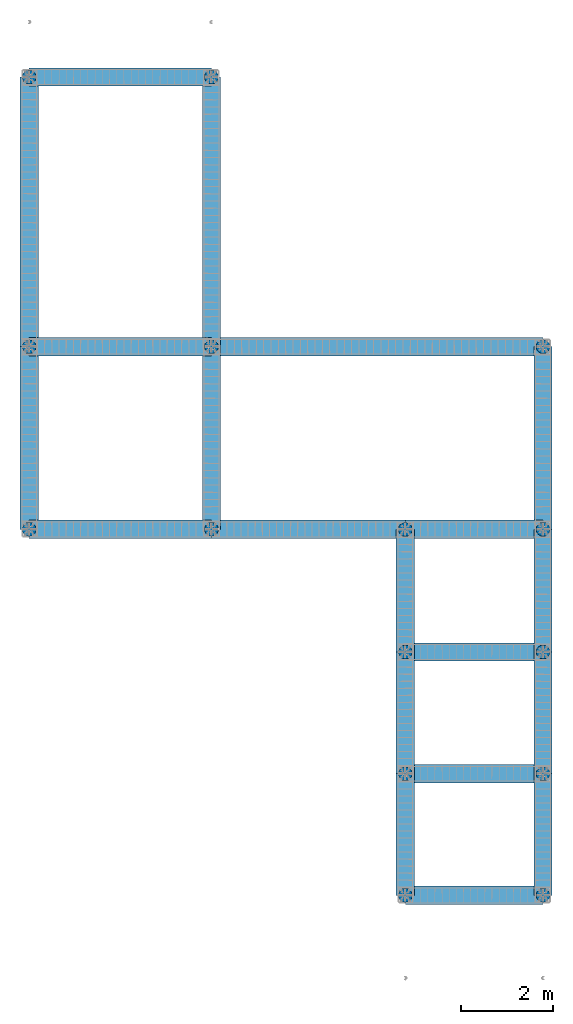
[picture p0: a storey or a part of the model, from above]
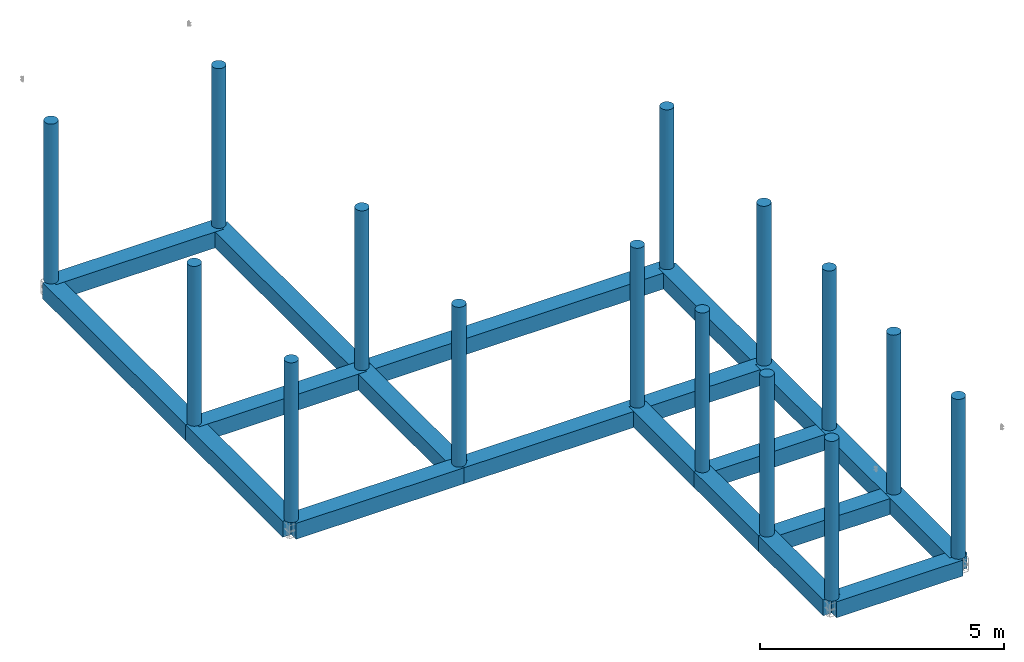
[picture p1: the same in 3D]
Properties of the parts of a building model (IFC4), part 1 of 2

# File
Description: ViewDefinition [CoordinationView]
Made in: IFC file generated by ModeSt (Tecnisoft s.a.s.)

# IfcBuildingStorey (2)
In: Tettoia
Name | Elevation (m)
Storey 0 | 0
Storey 1 | 4.2

# IfcBeam: 2 TRAVE 40X40 (20)
In: Storey 0
Type - PredefinedType: BEAM; Material: Calcestruzzo classe C25/30
Description: 2 TRAVE 40X40 - Cemento armato
Pset_BeamCommon - LoadBearing: yes
BaseQuantities - ?: 0.16 m2
Name | BaseQuantities, ? (m3) | BaseQuantities, ? (m)
406 | 0.6352 | 3.97
410 | 0.6368 | 3.98
405 | 0.48 | 3
404 | 0.48 | 3
403 | 0.48 | 3
402 | 0.48 | 3
2 x 412 | 0.424 | 2.65
412 | 0.4272 | 2.67
412 | 0.6368 | 3.98
406 | 1.1552 | 7.22
410 | 0.9392 | 5.87
407 | 0.6352 | 3.97
409 | 0.9392 | 5.87
409 | 0.6368 | 3.98
405 | 0.6352 | 3.97
405 | 0.6752 | 4.22
411 | 0.4272 | 2.67
2 x 411 | 0.424 | 2.65

# IfcBeam: 3 IPE160 (6)
In: Storey 1
Type - PredefinedType: BEAM; Material: Acciaio
Description: 3 IPE160 - Acciaio
Pset_BeamCommon - LoadBearing: yes
BaseQuantities - ?: 0.0019396 m2
Name | BaseQuantities, ? (m3) | BaseQuantities, ? (m)
102 | 0.0058188 | 3
101 | 0.0058188 | 3
107 | 0.00770022 | 3.97
108 | 0.00770022 | 3.97
104 | 0.0058188 | 3
103 | 0.0058188 | 3

# IfcBeam: 9 IPE200 (28)
In: Storey 1
Type - PredefinedType: BEAM; Material: Acciaio
Description: 9 IPE200 - Acciaio
Pset_BeamCommon - LoadBearing: yes
BaseQuantities - ?: 0.0027248 m2
Name | BaseQuantities, ? (m3) | BaseQuantities, ? (m)
106 | 0.0108175 | 3.97
109 | 0.00799729 | 2.935
106 | 0.0081744 | 3
110 | 0.00381472 | 1.4
110 | 0.00799729 | 2.935
109 | 0.0108447 | 3.98
105 | 0.0108175 | 3.97
105 | 0.0114987 | 4.22
110 | 0.0108447 | 3.98
109 | 0.00381472 | 1.4
110 | 0.00799728 | 2.935
109 | 0.00799728 | 2.935
2 x 112 | 0.00361036 | 1.325
105 | 0.0081744 | 3
111 | 0.00727521 | 2.67
2 x 111 | 0.00361036 | 1.325
111 | 0.00722072 | 2.65
111 | 0.0054496 | 2
112 | 0.0108447 | 3.98
112 | 0.00727521 | 2.67
105 | 0.00054496 | 0.2
112 | 0.000544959 | 0.2
111 | 0.0108447 | 3.98
106 | 0.0114987 | 4.22
112 | 0.00722072 | 2.65
112 | 0.0054496 | 2

# IfcColumn: 1 PILASTRO D30 (15)
In: Storey 0
Type - PredefinedType: COLUMN; Material: Calcestruzzo classe C25/30
Description: 1 PILASTRO D30 - Cemento armato
Pset_ColumnCommon - LoadBearing: yes
BaseQuantities - ?: 0.0695288 m2; ?: 0.278115 m3; ?: 4 m
Name
5
6
4
3
8
12
13
15
14
1
9
22
23
2
26

# IfcColumn: 4 CC101x5 (15)
In: Storey 1
Type - PredefinedType: COLUMN; Material: Acciaio
Description: 4 CC101x5 - Acciaio
Pset_ColumnCommon - LoadBearing: yes
BaseQuantities - ?: 0.00148328 m2; ?: 0.000296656 m3; ?: 0.2 m
Name
16
17
18
19
11
7
20
21
10
24
25
27
28
29
30

# IfcFastener: Collegamento -001_0101 (40)
In: Storey 1
Type - PredefinedType: WELD
Description: 7x7

# IfcFastener: Collegamento -002_0102 (40)
In: Storey 1
Type - PredefinedType: WELD
Description: 7x7

# IfcFastener: Collegamento -003_0103 (40)
In: Storey 1
Type - PredefinedType: WELD
Description: 7x7

# IfcFastener: Collegamento -004_0104 (40)
In: Storey 1
Type - PredefinedType: WELD
Description: 7x7

# IfcFastener: Collegamento -005_0105 (40)
In: Storey 1
Type - PredefinedType: WELD
Description: 7x7

# IfcFastener: Collegamento -006_0106 (40)
In: Storey 1
Type - PredefinedType: WELD
Description: 7x7

# IfcFastener: Collegamento -007_0107 (40)
In: Storey 1
Type - PredefinedType: WELD
Description: 7x7

# IfcFastener: Collegamento -008_0108 (40)
In: Storey 1
Type - PredefinedType: WELD
Description: 7x7

# IfcFastener: Collegamento -009_0109 (40)
In: Storey 1
Type - PredefinedType: WELD
Description: 7x7

# IfcFastener: Collegamento -010_0110 (40)
In: Storey 1
Type - PredefinedType: WELD
Description: 7x7

# IfcFastener: Collegamento -011_0111 (40)
In: Storey 1
Type - PredefinedType: WELD
Description: 7x7

# IfcFastener: Collegamento -012_0112 (40)
In: Storey 1
Type - PredefinedType: WELD
Description: 7x7

# IfcFastener: Collegamento -013_0113 (40)
In: Storey 1
Type - PredefinedType: WELD
Description: 7x7

# IfcFastener: Collegamento -014_0114 (40)
In: Storey 1
Type - PredefinedType: WELD
Description: 7x7

# IfcFastener: Collegamento -015_0115 (40)
In: Storey 1
Type - PredefinedType: WELD
Description: 7x7

# IfcFastener: Collegamento 0101_-001 (40)
In: Storey 1
Type - PredefinedType: WELD
Description: 7x7

# IfcFastener: Collegamento 0102_-002 (40)
In: Storey 1
Type - PredefinedType: WELD
Description: 7x7

# IfcFastener: Collegamento 0103_-003 (40)
In: Storey 1
Type - PredefinedType: WELD
Description: 7x7

# IfcFastener: Collegamento 0104_-004 (40)
In: Storey 1
Type - PredefinedType: WELD
Description: 7x7

# IfcFastener: Collegamento 0105_-005 (40)
In: Storey 1
Type - PredefinedType: WELD
Description: 7x7

# IfcFastener: Collegamento 0106_-006 (40)
In: Storey 1
Type - PredefinedType: WELD
Description: 7x7

# IfcFastener: Collegamento 0107_-007 (40)
In: Storey 1
Type - PredefinedType: WELD
Description: 7x7

# IfcFastener: Collegamento 0108_-008 (40)
In: Storey 1
Type - PredefinedType: WELD
Description: 7x7

# IfcFastener: Collegamento 0109_-009 (40)
In: Storey 1
Type - PredefinedType: WELD
Description: 7x7

# IfcFastener: Collegamento 0110_-010 (40)
In: Storey 1
Type - PredefinedType: WELD
Description: 7x7

# IfcFastener: Collegamento 0111_-011 (40)
In: Storey 1
Type - PredefinedType: WELD
Description: 7x7

# IfcFastener: Collegamento 0112_-012 (40)
In: Storey 1
Type - PredefinedType: WELD
Description: 7x7

# IfcFastener: Collegamento 0113_-013 (40)
In: Storey 1
Type - PredefinedType: WELD
Description: 7x7

# IfcFastener: Collegamento 0114_-014 (40)
In: Storey 1
Type - PredefinedType: WELD
Description: 7x7

# IfcFastener: Collegamento 0115_-015 (40)
In: Storey 1
Type - PredefinedType: WELD
Description: 7x7

# IfcMechanicalFastener: Collegamento -001_0101 (30)
In: Storey 1
Type - PredefinedType: BOLT
Name | Description | NominalDiameter (m)
18 x Collegamento -001_0101 | M12 | 0.0119999
12 x Collegamento -001_0101 | M24 | 0.024

# IfcMechanicalFastener: Collegamento -002_0102 (30)
In: Storey 1
Type - PredefinedType: BOLT
Name | Description | NominalDiameter (m)
18 x Collegamento -002_0102 | M12 | 0.0119999
12 x Collegamento -002_0102 | M24 | 0.024

# IfcMechanicalFastener: Collegamento -003_0103 (30)
In: Storey 1
Type - PredefinedType: BOLT
Name | Description | NominalDiameter (m)
18 x Collegamento -003_0103 | M12 | 0.0119999
12 x Collegamento -003_0103 | M24 | 0.024

# IfcMechanicalFastener: Collegamento -004_0104 (30)
In: Storey 1
Type - PredefinedType: BOLT
Name | Description | NominalDiameter (m)
18 x Collegamento -004_0104 | M12 | 0.0119999
12 x Collegamento -004_0104 | M24 | 0.024

# IfcMechanicalFastener: Collegamento -005_0105 (30)
In: Storey 1
Type - PredefinedType: BOLT
Name | Description | NominalDiameter (m)
18 x Collegamento -005_0105 | M12 | 0.0119999
12 x Collegamento -005_0105 | M24 | 0.024

# IfcMechanicalFastener: Collegamento -006_0106 (30)
In: Storey 1
Type - PredefinedType: BOLT
Name | Description | NominalDiameter (m)
18 x Collegamento -006_0106 | M12 | 0.0119999
12 x Collegamento -006_0106 | M24 | 0.024

# IfcMechanicalFastener: Collegamento -007_0107 (30)
In: Storey 1
Type - PredefinedType: BOLT
Name | Description | NominalDiameter (m)
6 x Collegamento -007_0107 | M12 | 0.0119991
12 x Collegamento -007_0107 | M24 | 0.024
12 x Collegamento -007_0107 | M12 | 0.0119998

# IfcMechanicalFastener: Collegamento -008_0108 (30)
In: Storey 1
Type - PredefinedType: BOLT
Name | Description | NominalDiameter (m)
6 x Collegamento -008_0108 | M12 | 0.0119991
12 x Collegamento -008_0108 | M24 | 0.024
12 x Collegamento -008_0108 | M12 | 0.0119997

# IfcMechanicalFastener: Collegamento -009_0109 (30)
In: Storey 1
Type - PredefinedType: BOLT
Name | Description | NominalDiameter (m)
6 x Collegamento -009_0109 | M12 | 0.0119991
12 x Collegamento -009_0109 | M24 | 0.024
12 x Collegamento -009_0109 | M12 | 0.0119997

# IfcMechanicalFastener: Collegamento -010_0110 (30)
In: Storey 1
Type - PredefinedType: BOLT
Name | Description | NominalDiameter (m)
6 x Collegamento -010_0110 | M12 | 0.0119991
12 x Collegamento -010_0110 | M24 | 0.024
12 x Collegamento -010_0110 | M12 | 0.0119997

# IfcMechanicalFastener: Collegamento -011_0111 (30)
In: Storey 1
Type - PredefinedType: BOLT
Name | Description | NominalDiameter (m)
6 x Collegamento -011_0111 | M12 | 0.0119991
12 x Collegamento -011_0111 | M24 | 0.024
12 x Collegamento -011_0111 | M12 | 0.0119998

# IfcMechanicalFastener: Collegamento -012_0112 (30)
In: Storey 1
Type - PredefinedType: BOLT
Name | Description | NominalDiameter (m)
6 x Collegamento -012_0112 | M12 | 0.0119991
12 x Collegamento -012_0112 | M24 | 0.024
12 x Collegamento -012_0112 | M12 | 0.0119997

# IfcMechanicalFastener: Collegamento -013_0113 (30)
In: Storey 1
Type - PredefinedType: BOLT
Name | Description | NominalDiameter (m)
6 x Collegamento -013_0113 | M12 | 0.0119991
12 x Collegamento -013_0113 | M24 | 0.024
12 x Collegamento -013_0113 | M12 | 0.0119997

# IfcMechanicalFastener: Collegamento -014_0114 (30)
In: Storey 1
Type - PredefinedType: BOLT
Name | Description | NominalDiameter (m)
6 x Collegamento -014_0114 | M12 | 0.0119993
12 x Collegamento -014_0114 | M24 | 0.024
12 x Collegamento -014_0114 | M12 | 0.0119991

# IfcMechanicalFastener: Collegamento -015_0115 (30)
In: Storey 1
Type - PredefinedType: BOLT
Name | Description | NominalDiameter (m)
6 x Collegamento -015_0115 | M12 | 0.0119992
12 x Collegamento -015_0115 | M24 | 0.024
12 x Collegamento -015_0115 | M12 | 0.0119991

# IfcMechanicalFastener: Collegamento -016_0109 (32)
In: Storey 1
Type - PredefinedType: BOLT
Name | Description | NominalDiameter (m)
16 x Collegamento -016_0109 | M12 | 0.0119997
8 x Collegamento -016_0109 | M12 | 0.012
8 x Collegamento -016_0109 | M24 | 0.024

# IfcMechanicalFastener: Collegamento 0101_-001 (16)
In: Storey 1
Type - PredefinedType: BOLT
Name | Description | NominalDiameter (m)
4 x Collegamento 0101_-001 | M12 | 0.0119998
4 x Collegamento 0101_-001 | M12 | 0.012
4 x Collegamento 0101_-001 | M24 | 0.024
4 x Collegamento 0101_-001 | M12 | 0.0119999

# IfcMechanicalFastener: Collegamento 0101_0102 (32)
In: Storey 1
Type - PredefinedType: BOLT
Name | Description | NominalDiameter (m)
8 x Collegamento 0101_0102 | M12 | 0.0119997
8 x Collegamento 0101_0102 | M12 | 0.012
8 x Collegamento 0101_0102 | M24 | 0.024
8 x Collegamento 0101_0102 | M12 | 0.0119999

# IfcMechanicalFastener: Collegamento 0102_-002 (16)
In: Storey 1
Type - PredefinedType: BOLT
Name | Description | NominalDiameter (m)
4 x Collegamento 0102_-002 | M12 | 0.0119998
4 x Collegamento 0102_-002 | M12 | 0.012
4 x Collegamento 0102_-002 | M24 | 0.024
4 x Collegamento 0102_-002 | M12 | 0.0119999

# IfcMechanicalFastener: Collegamento 0102_0101 (32)
In: Storey 1
Type - PredefinedType: BOLT
Name | Description | NominalDiameter (m)
8 x Collegamento 0102_0101 | M12 | 0.0119997
8 x Collegamento 0102_0101 | M12 | 0.012
8 x Collegamento 0102_0101 | M24 | 0.024
8 x Collegamento 0102_0101 | M12 | 0.0119999

# IfcMechanicalFastener: Collegamento 0103_-003 (16)
In: Storey 1
Type - PredefinedType: BOLT
Name | Description | NominalDiameter (m)
8 x Collegamento 0103_-003 | M12 | 0.0119999
4 x Collegamento 0103_-003 | M12 | 0.012
4 x Collegamento 0103_-003 | M24 | 0.024

# IfcMechanicalFastener: Collegamento 0103_0104 (32)
In: Storey 1
Type - PredefinedType: BOLT
Name | Description | NominalDiameter (m)
8 x Collegamento 0103_0104 | M12 | 0.0119997
8 x Collegamento 0103_0104 | M12 | 0.012
8 x Collegamento 0103_0104 | M24 | 0.024
8 x Collegamento 0103_0104 | M12 | 0.0119996

# IfcMechanicalFastener: Collegamento 0104_-004 (16)
In: Storey 1
Type - PredefinedType: BOLT
Name | Description | NominalDiameter (m)
8 x Collegamento 0104_-004 | M12 | 0.0119999
4 x Collegamento 0104_-004 | M12 | 0.012
4 x Collegamento 0104_-004 | M24 | 0.024

# IfcMechanicalFastener: Collegamento 0104_0103 (32)
In: Storey 1
Type - PredefinedType: BOLT
Name | Description | NominalDiameter (m)
8 x Collegamento 0104_0103 | M12 | 0.0119997
8 x Collegamento 0104_0103 | M12 | 0.012
8 x Collegamento 0104_0103 | M24 | 0.024
8 x Collegamento 0104_0103 | M12 | 0.0119996

# IfcMechanicalFastener: Collegamento 0105_-005 (16)
In: Storey 1
Type - PredefinedType: BOLT
Name | Description | NominalDiameter (m)
8 x Collegamento 0105_-005 | M12 | 0.0119999
4 x Collegamento 0105_-005 | M12 | 0.012
4 x Collegamento 0105_-005 | M24 | 0.024

# IfcMechanicalFastener: Collegamento 0105_0106 (32)
In: Storey 1
Type - PredefinedType: BOLT
Name | Description | NominalDiameter (m)
8 x Collegamento 0105_0106 | M12 | 0.0119997
8 x Collegamento 0105_0106 | M12 | 0.012
8 x Collegamento 0105_0106 | M24 | 0.024
8 x Collegamento 0105_0106 | M12 | 0.0119996

# IfcMechanicalFastener: Collegamento 0106_-006 (16)
In: Storey 1
Type - PredefinedType: BOLT
Name | Description | NominalDiameter (m)
8 x Collegamento 0106_-006 | M12 | 0.0119999
4 x Collegamento 0106_-006 | M12 | 0.012
4 x Collegamento 0106_-006 | M24 | 0.024

# IfcMechanicalFastener: Collegamento 0106_0105 (32)
In: Storey 1
Type - PredefinedType: BOLT
Name | Description | NominalDiameter (m)
8 x Collegamento 0106_0105 | M12 | 0.0119997
8 x Collegamento 0106_0105 | M12 | 0.012
8 x Collegamento 0106_0105 | M24 | 0.024
8 x Collegamento 0106_0105 | M12 | 0.0119996

# IfcMechanicalFastener: Collegamento 0107_-007 (16)
In: Storey 1
Type - PredefinedType: BOLT
Name | Description | NominalDiameter (m)
8 x Collegamento 0107_-007 | M12 | 0.0119998
4 x Collegamento 0107_-007 | M12 | 0.012
4 x Collegamento 0107_-007 | M24 | 0.024

# IfcMechanicalFastener: Collegamento 0107_0111 (32)
In: Storey 1
Type - PredefinedType: BOLT
Name | Description | NominalDiameter (m)
8 x Collegamento 0107_0111 | M12 | 0.0119997
8 x Collegamento 0107_0111 | M12 | 0.012
8 x Collegamento 0107_0111 | M24 | 0.024
8 x Collegamento 0107_0111 | M12 | 0.0119999

# IfcMechanicalFastener: Collegamento 0108_-008 (16)
In: Storey 1
Type - PredefinedType: BOLT
Name | Description | NominalDiameter (m)
8 x Collegamento 0108_-008 | M12 | 0.0119997
4 x Collegamento 0108_-008 | M12 | 0.012
4 x Collegamento 0108_-008 | M24 | 0.024

# IfcMechanicalFastener: Collegamento 0108_0112 (48)
In: Storey 1
Type - PredefinedType: BOLT
Name | Description | NominalDiameter (m)
12 x Collegamento 0108_0112 | M12 | 0.0119997
12 x Collegamento 0108_0112 | M12 | 0.012
12 x Collegamento 0108_0112 | M24 | 0.024
12 x Collegamento 0108_0112 | M12 | 0.0119999

# IfcMechanicalFastener: Collegamento 0109_-009 (16)
In: Storey 1
Type - PredefinedType: BOLT
Name | Description | NominalDiameter (m)
8 x Collegamento 0109_-009 | M12 | 0.0119997
4 x Collegamento 0109_-009 | M12 | 0.012
4 x Collegamento 0109_-009 | M24 | 0.024

# IfcMechanicalFastener: Collegamento 0109_0108 (32)
In: Storey 1
Type - PredefinedType: BOLT
Name | Description | NominalDiameter (m)
16 x Collegamento 0109_0108 | M12 | 0.0119997
8 x Collegamento 0109_0108 | M12 | 0.012
8 x Collegamento 0109_0108 | M24 | 0.024

# IfcMechanicalFastener: Collegamento 0109_0110 (32)
In: Storey 1
Type - PredefinedType: BOLT
Name | Description | NominalDiameter (m)
16 x Collegamento 0109_0110 | M12 | 0.0119997
8 x Collegamento 0109_0110 | M12 | 0.012
8 x Collegamento 0109_0110 | M24 | 0.024

# IfcMechanicalFastener: Collegamento 0110_-010 (16)
In: Storey 1
Type - PredefinedType: BOLT
Name | Description | NominalDiameter (m)
8 x Collegamento 0110_-010 | M12 | 0.0119997
4 x Collegamento 0110_-010 | M12 | 0.012
4 x Collegamento 0110_-010 | M24 | 0.024

# IfcMechanicalFastener: Collegamento 0110_0109 (32)
In: Storey 1
Type - PredefinedType: BOLT
Name | Description | NominalDiameter (m)
16 x Collegamento 0110_0109 | M12 | 0.0119997
8 x Collegamento 0110_0109 | M12 | 0.012
8 x Collegamento 0110_0109 | M24 | 0.024

# IfcMechanicalFastener: Collegamento 0111_-011 (16)
In: Storey 1
Type - PredefinedType: BOLT
Name | Description | NominalDiameter (m)
8 x Collegamento 0111_-011 | M12 | 0.0119998
4 x Collegamento 0111_-011 | M12 | 0.012
4 x Collegamento 0111_-011 | M24 | 0.024

# IfcMechanicalFastener: Collegamento 0111_0112 (32)
In: Storey 1
Type - PredefinedType: BOLT
Name | Description | NominalDiameter (m)
8 x Collegamento 0111_0112 | M12 | 0.0119999
8 x Collegamento 0111_0112 | M12 | 0.012
8 x Collegamento 0111_0112 | M24 | 0.024
8 x Collegamento 0111_0112 | M12 | 0.0119997

# IfcMechanicalFastener: Collegamento 0112_-012 (16)
In: Storey 1
Type - PredefinedType: BOLT
Name | Description | NominalDiameter (m)
8 x Collegamento 0112_-012 | M12 | 0.0119997
4 x Collegamento 0112_-012 | M12 | 0.012
4 x Collegamento 0112_-012 | M24 | 0.024

# IfcMechanicalFastener: Collegamento 0112_-016 (80)
In: Storey 1
Type - PredefinedType: BOLT
Name | Description | NominalDiameter (m)
12 x Collegamento 0112_-016 | M12 | 0.0119999
20 x Collegamento 0112_-016 | M12 | 0.012
20 x Collegamento 0112_-016 | M24 | 0.024
12 x Collegamento 0112_-016 | M12 | 0.0119996
16 x Collegamento 0112_-016 | M12 | 0.0119997

# IfcMechanicalFastener: Collegamento 0112_0111 (48)
In: Storey 1
Type - PredefinedType: BOLT
Name | Description | NominalDiameter (m)
8 x Collegamento 0112_0111 | M12 | 0.0119999
12 x Collegamento 0112_0111 | M12 | 0.012
12 x Collegamento 0112_0111 | M24 | 0.024
8 x Collegamento 0112_0111 | M12 | 0.0119998
8 x Collegamento 0112_0111 | M12 | 0.0119997

# IfcMechanicalFastener: Collegamento 0113_-013 (16)
In: Storey 1
Type - PredefinedType: BOLT
Name | Description | NominalDiameter (m)
8 x Collegamento 0113_-013 | M12 | 0.0119997
4 x Collegamento 0113_-013 | M12 | 0.012
4 x Collegamento 0113_-013 | M24 | 0.024

# IfcMechanicalFastener: Collegamento 0113_-016 (48)
In: Storey 1
Type - PredefinedType: BOLT
Name | Description | NominalDiameter (m)
24 x Collegamento 0113_-016 | M12 | 0.0119997
12 x Collegamento 0113_-016 | M12 | 0.012
12 x Collegamento 0113_-016 | M24 | 0.024

# IfcMechanicalFastener: Collegamento 0114_-014 (16)
In: Storey 1
Type - PredefinedType: BOLT
Name | Description | NominalDiameter (m)
8 x Collegamento 0114_-014 | M12 | 0.0119991
4 x Collegamento 0114_-014 | M12 | 0.012
4 x Collegamento 0114_-014 | M24 | 0.024

# IfcMechanicalFastener: Collegamento 0114_0115 (32)
In: Storey 1
Type - PredefinedType: BOLT
Name | Description | NominalDiameter (m)
8 x Collegamento 0114_0115 | M12 | 0.0119999
8 x Collegamento 0114_0115 | M12 | 0.012
8 x Collegamento 0114_0115 | M24 | 0.024
8 x Collegamento 0114_0115 | M12 | 0.0119991

# IfcMechanicalFastener: Collegamento 0115_-015 (16)
In: Storey 1
Type - PredefinedType: BOLT
Name | Description | NominalDiameter (m)
8 x Collegamento 0115_-015 | M12 | 0.0119991
4 x Collegamento 0115_-015 | M12 | 0.012
4 x Collegamento 0115_-015 | M24 | 0.024

# IfcMechanicalFastener: Collegamento 0115_0114 (32)
In: Storey 1
Type - PredefinedType: BOLT
Name | Description | NominalDiameter (m)
8 x Collegamento 0115_0114 | M12 | 0.0119997
8 x Collegamento 0115_0114 | M12 | 0.012
8 x Collegamento 0115_0114 | M24 | 0.024
8 x Collegamento 0115_0114 | M12 | 0.0119991

# IfcMechanicalFastener: Collegamento 0116_0117 (32)
In: Storey 0
Type - PredefinedType: BOLT
Name | Description | NominalDiameter (m)
8 x Collegamento 0116_0117 | M12 | 0.0119997
8 x Collegamento 0116_0117 | M12 | 0.012
8 x Collegamento 0116_0117 | M24 | 0.024
8 x Collegamento 0116_0117 | M12 | 0.0119999

# IfcMechanicalFastener: Collegamento 0117_0116 (32)
In: Storey 0
Type - PredefinedType: BOLT
Name | Description | NominalDiameter (m)
8 x Collegamento 0117_0116 | M12 | 0.0119997
8 x Collegamento 0117_0116 | M12 | 0.012
8 x Collegamento 0117_0116 | M24 | 0.024
8 x Collegamento 0117_0116 | M12 | 0.0119999

# IfcMechanicalFastener: Collegamento 0118_0103 (24)
In: Storey 1
Type - PredefinedType: BOLT
Name | Description | NominalDiameter (m)
8 x Collegamento 0118_0103 | M12 | 0.0119997
6 x Collegamento 0118_0103 | M12 | 0.012
6 x Collegamento 0118_0103 | M24 | 0.024
4 x Collegamento 0118_0103 | M12 | 0.0119999

# IfcMechanicalFastener: Collegamento 0119_0104 (24)
In: Storey 1
Type - PredefinedType: BOLT
Name | Description | NominalDiameter (m)
8 x Collegamento 0119_0104 | M12 | 0.0119997
6 x Collegamento 0119_0104 | M12 | 0.012
6 x Collegamento 0119_0104 | M24 | 0.024
4 x Collegamento 0119_0104 | M12 | 0.0119999

# IfcMechanicalFastener: Collegamento 0122_0114 (72)
In: Storey 1
Type - PredefinedType: BOLT
Name | Description | NominalDiameter (m)
24 x Collegamento 0122_0114 | M12 | 0.0119991
18 x Collegamento 0122_0114 | M12 | 0.012
18 x Collegamento 0122_0114 | M24 | 0.024
12 x Collegamento 0122_0114 | M12 | 0.0119992

# IfcMechanicalFastener: Collegamento 0123_0115 (48)
In: Storey 1
Type - PredefinedType: BOLT
Name | Description | NominalDiameter (m)
16 x Collegamento 0123_0115 | M12 | 0.0119991
12 x Collegamento 0123_0115 | M12 | 0.012
12 x Collegamento 0123_0115 | M24 | 0.024
8 x Collegamento 0123_0115 | M12 | 0.0119992

# IfcMechanicalFastener: Collegamento 0124_0125 (32)
In: Storey 0
Type - PredefinedType: BOLT
Name | Description | NominalDiameter (m)
8 x Collegamento 0124_0125 | M12 | 0.0119999
8 x Collegamento 0124_0125 | M12 | 0.012
8 x Collegamento 0124_0125 | M24 | 0.024
8 x Collegamento 0124_0125 | M12 | 0.0119991

# IfcMechanicalFastener: Collegamento 0125_0124 (32)
In: Storey 0
Type - PredefinedType: BOLT
Name | Description | NominalDiameter (m)
8 x Collegamento 0125_0124 | M12 | 0.0119997
8 x Collegamento 0125_0124 | M12 | 0.012
8 x Collegamento 0125_0124 | M24 | 0.024
8 x Collegamento 0125_0124 | M12 | 0.0119991

# IfcPlate: Collegamento -001_0101
In: Storey 1
Type - PredefinedType: SHEET

# IfcPlate: Collegamento -002_0102
In: Storey 1
Type - PredefinedType: SHEET

# IfcPlate: Collegamento -003_0103
In: Storey 1
Type - PredefinedType: SHEET

# IfcPlate: Collegamento -004_0104
In: Storey 1
Type - PredefinedType: SHEET

# IfcPlate: Collegamento -005_0105
In: Storey 1
Type - PredefinedType: SHEET

# IfcPlate: Collegamento -006_0106
In: Storey 1
Type - PredefinedType: SHEET

# IfcPlate: Collegamento -007_0107
In: Storey 1
Type - PredefinedType: SHEET

# IfcPlate: Collegamento -008_0108
In: Storey 1
Type - PredefinedType: SHEET

# IfcPlate: Collegamento -009_0109
In: Storey 1
Type - PredefinedType: SHEET

# IfcPlate: Collegamento -010_0110
In: Storey 1
Type - PredefinedType: SHEET

# IfcPlate: Collegamento -011_0111
In: Storey 1
Type - PredefinedType: SHEET

# IfcPlate: Collegamento -012_0112
In: Storey 1
Type - PredefinedType: SHEET

# IfcPlate: Collegamento -013_0113
In: Storey 1
Type - PredefinedType: SHEET

# IfcPlate: Collegamento -014_0114
In: Storey 1
Type - PredefinedType: SHEET

# IfcPlate: Collegamento -015_0115
In: Storey 1
Type - PredefinedType: SHEET

# IfcPlate: Collegamento -016_0109 (2)
In: Storey 1
Type - PredefinedType: SHEET

# IfcPlate: Collegamento 0101_-001
In: Storey 1
Type - PredefinedType: SHEET

# IfcPlate: Collegamento 0101_0102 (2)
In: Storey 1
Type - PredefinedType: SHEET

# IfcPlate: Collegamento 0102_-002
In: Storey 1
Type - PredefinedType: SHEET

# IfcPlate: Collegamento 0102_0101 (2)
In: Storey 1
Type - PredefinedType: SHEET

# IfcPlate: Collegamento 0103_-003
In: Storey 1
Type - PredefinedType: SHEET

# IfcPlate: Collegamento 0103_0104 (2)
In: Storey 1
Type - PredefinedType: SHEET

# IfcPlate: Collegamento 0104_-004
In: Storey 1
Type - PredefinedType: SHEET

# IfcPlate: Collegamento 0104_0103 (2)
In: Storey 1
Type - PredefinedType: SHEET

# IfcPlate: Collegamento 0105_-005
In: Storey 1
Type - PredefinedType: SHEET

# IfcPlate: Collegamento 0105_0106 (2)
In: Storey 1
Type - PredefinedType: SHEET

# IfcPlate: Collegamento 0106_-006
In: Storey 1
Type - PredefinedType: SHEET

# IfcPlate: Collegamento 0106_0105 (2)
In: Storey 1
Type - PredefinedType: SHEET

# IfcPlate: Collegamento 0107_-007
In: Storey 1
Type - PredefinedType: SHEET

# IfcPlate: Collegamento 0107_0111 (2)
In: Storey 1
Type - PredefinedType: SHEET

# IfcPlate: Collegamento 0108_-008
In: Storey 1
Type - PredefinedType: SHEET

# IfcPlate: Collegamento 0108_0112 (2)
In: Storey 1
Type - PredefinedType: SHEET

# IfcPlate: Collegamento 0109_-009
In: Storey 1
Type - PredefinedType: SHEET

# IfcPlate: Collegamento 0109_0108 (2)
In: Storey 1
Type - PredefinedType: SHEET

# IfcPlate: Collegamento 0109_0110 (2)
In: Storey 1
Type - PredefinedType: SHEET

# IfcPlate: Collegamento 0110_-010
In: Storey 1
Type - PredefinedType: SHEET

# IfcPlate: Collegamento 0110_0109 (2)
In: Storey 1
Type - PredefinedType: SHEET

# IfcPlate: Collegamento 0111_-011
In: Storey 1
Type - PredefinedType: SHEET

# IfcPlate: Collegamento 0111_0112 (2)
In: Storey 1
Type - PredefinedType: SHEET

# IfcPlate: Collegamento 0112_-012
In: Storey 1
Type - PredefinedType: SHEET

# IfcPlate: Collegamento 0112_-016 (2)
In: Storey 1
Type - PredefinedType: SHEET

# IfcPlate: Collegamento 0112_0111 (2)
In: Storey 1
Type - PredefinedType: SHEET

# IfcPlate: Collegamento 0113_-013
In: Storey 1
Type - PredefinedType: SHEET

# IfcPlate: Collegamento 0113_-016 (2)
In: Storey 1
Type - PredefinedType: SHEET

# IfcPlate: Collegamento 0114_-014
In: Storey 1
Type - PredefinedType: SHEET

# IfcPlate: Collegamento 0114_0115 (2)
In: Storey 1
Type - PredefinedType: SHEET

# IfcPlate: Collegamento 0115_-015
In: Storey 1
Type - PredefinedType: SHEET

# IfcPlate: Collegamento 0115_0114 (2)
In: Storey 1
Type - PredefinedType: SHEET

# IfcPlate: Collegamento 0116_0117 (2)
In: Storey 0
Type - PredefinedType: SHEET

# IfcPlate: Collegamento 0117_0116 (2)
In: Storey 0
Type - PredefinedType: SHEET

# IfcPlate: Collegamento 0118_0103 (2)
In: Storey 1
Type - PredefinedType: SHEET

# IfcPlate: Collegamento 0119_0104 (2)
In: Storey 1
Type - PredefinedType: SHEET

# IfcPlate: Collegamento 0122_0114 (2)
In: Storey 1
Type - PredefinedType: SHEET

# IfcPlate: Collegamento 0123_0115 (2)
In: Storey 1
Type - PredefinedType: SHEET

# IfcPlate: Collegamento 0124_0125 (2)
In: Storey 0
Type - PredefinedType: SHEET

# IfcPlate: Collegamento 0125_0124 (2)
In: Storey 0
Type - PredefinedType: SHEET

# IfcReinforcingBar (150)
Name | In | NominalDiameter (m) | CrossSectionArea (m2) | BarLength (m) | SteelGrade
13 x  | Storey 1 | 0.012 | 0.0001131 | 0.423
12 x  | Storey 1 | 0.012 | 0.0001131 | 0.0140465
15 x  | Storey 1 | 0.012 | 0.0001131 | 0.0359998
 | Storey 1 | 0.012 | 0.0001131 | 0.418
3 x  | Storey 1 | 0.012 | 0.0001131 | 0.0140464
 | Storey 1 | 0.012 | 0.0001131 | 0.425
15 x  | Storey 0 | 0.014 | 0.00015394 | 0.97063 | B450C
15 x  | Storey 0 | 0.014 | 0.00015394 | 4.03463 | B450C
8 x  | Storey 0 | 0.008 | 0.000050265 | 1.00815 | B450C
7 x  | Storey 0 | 0.008 | 0.000050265 | 1.00814 | B450C
10 x  | Storey 0 | 0.008 | 0.000050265 | 1.5868 | B450C
3 x  | Storey 0 | 0.012 | 0.0001131 | 3.77121 | B450C
6 x  | Storey 0 | 0.016 | 0.00020106 | 2.46833 | B450C
2 x  | Storey 0 | 0.012 | 0.0001131 | 4.69121 | B450C
 | Storey 0 | 0.012 | 0.0001131 | 4.89121 | B450C
 | Storey 0 | 0.012 | 0.0001131 | 3.72121 | B450C
 | Storey 0 | 0.016 | 0.00020106 | 4.85045 | B450C
 | Storey 0 | 0.016 | 0.00020106 | 5.33546 | B450C
 | Storey 0 | 0.016 | 0.00020106 | 2.39333 | B450C
2 x  | Storey 0 | 0.016 | 0.00020106 | 2.87833 | B450C
 | Storey 0 | 0.012 | 0.0001131 | 7.94121 | B450C
 | Storey 0 | 0.016 | 0.00020106 | 6.91046 | B450C
 | Storey 0 | 0.016 | 0.00020106 | 4.50333 | B450C
 | Storey 0 | 0.012 | 0.0001131 | 4.74121 | B450C
2 x  | Storey 0 | 0.016 | 0.00020106 | 2.95333 | B450C
3 x  | Storey 0 | 0.012 | 0.0001131 | 4.70121 | B450C
2 x  | Storey 0 | 0.012 | 0.0001131 | 6.59121 | B450C
2 x  | Storey 0 | 0.016 | 0.00020106 | 6.24045 | B450C
2 x  | Storey 0 | 0.016 | 0.00020106 | 3.82834 | B450C
3 x  | Storey 0 | 0.016 | 0.00020106 | 2.88333 | B450C
2 x  | Storey 0 | 0.012 | 0.0001131 | 3.37121 | B450C
2 x  | Storey 0 | 0.012 | 0.0001131 | 3.32121 | B450C
 | Storey 0 | 0.012 | 0.0001131 | 3.39121 | B450C
 | Storey 0 | 0.016 | 0.00020106 | 3.90045 | B450C
2 x  | Storey 0 | 0.016 | 0.00020106 | 3.89046 | B450C
 | Storey 0 | 0.016 | 0.00020106 | 2.22833 | B450C
2 x  | Storey 0 | 0.016 | 0.00020106 | 2.21833 | B450C
 | Storey 0 | 0.012 | 0.0001131 | 3.34121 | B450C
 | Storey 0 | 0.016 | 0.00020106 | 3.82545 | B450C
 | Storey 0 | 0.016 | 0.00020106 | 4.56545 | B450C

# IfcSlab: 1 COPERTURA OMBREGGIANTE (9)
In: Storey 1
Type - PredefinedType: FLOOR; Material: Concrete
Description: 1 COPERTURA OMBREGGIANTE - Altezza solaio 0.030000 - Spessore cappa 0.030000 -
Pset_SlabCommon - LoadBearing: yes
BaseQuantities - ?: 0.03 m
Name | BaseQuantities, ? (m2) | BaseQuantities, ? (m3)
100 | 5.558 | 0.16674
101 | 23.3039 | 0.699117
102 | 15.8006 | 0.474018
103 | 7.95 | 0.2385
104 | 7.95 | 0.2385
105 | 6 | 0.18
106 | 16.7956 | 0.503868
107 | 11.94 | 0.3582
108 | 8.01 | 0.2403

# IfcReinforcingBarType, no part of this type: type
PredefinedType: MAIN; NominalDiameter: 0.012 m; CrossSectionArea: 0.0001131 m2; BarLength: 0.423 m; Material: Steel

# IfcReinforcingBarType, no part of this type: type
PredefinedType: MAIN; NominalDiameter: 0.012 m; CrossSectionArea: 0.0001131 m2; BarLength: 0.0140465 m; Material: Steel

# IfcReinforcingBarType, no part of this type: type
PredefinedType: MAIN; NominalDiameter: 0.012 m; CrossSectionArea: 0.0001131 m2; BarLength: 0.0359998 m; Material: Steel

# IfcReinforcingBarType, no part of this type: type
PredefinedType: MAIN; NominalDiameter: 0.012 m; CrossSectionArea: 0.0001131 m2; BarLength: 0.423 m; Material: Steel

# IfcReinforcingBarType, no part of this type: type
PredefinedType: MAIN; NominalDiameter: 0.012 m; CrossSectionArea: 0.0001131 m2; BarLength: 0.0140465 m; Material: Steel

# IfcReinforcingBarType, no part of this type: type
PredefinedType: MAIN; NominalDiameter: 0.012 m; CrossSectionArea: 0.0001131 m2; BarLength: 0.0359998 m; Material: Steel

# IfcReinforcingBarType, no part of this type: type
PredefinedType: MAIN; NominalDiameter: 0.012 m; CrossSectionArea: 0.0001131 m2; BarLength: 0.423 m; Material: Steel

# IfcReinforcingBarType, no part of this type: type
PredefinedType: MAIN; NominalDiameter: 0.012 m; CrossSectionArea: 0.0001131 m2; BarLength: 0.0140465 m; Material: Steel

# IfcReinforcingBarType, no part of this type: type
PredefinedType: MAIN; NominalDiameter: 0.012 m; CrossSectionArea: 0.0001131 m2; BarLength: 0.0359998 m; Material: Steel

# IfcReinforcingBarType, no part of this type: type
PredefinedType: MAIN; NominalDiameter: 0.012 m; CrossSectionArea: 0.0001131 m2; BarLength: 0.423 m; Material: Steel

# IfcReinforcingBarType, no part of this type: type
PredefinedType: MAIN; NominalDiameter: 0.012 m; CrossSectionArea: 0.0001131 m2; BarLength: 0.0140465 m; Material: Steel

# IfcReinforcingBarType, no part of this type: type
PredefinedType: MAIN; NominalDiameter: 0.012 m; CrossSectionArea: 0.0001131 m2; BarLength: 0.0359998 m; Material: Steel

# IfcReinforcingBarType, no part of this type: type
PredefinedType: MAIN; NominalDiameter: 0.012 m; CrossSectionArea: 0.0001131 m2; BarLength: 0.423 m; Material: Steel

# IfcReinforcingBarType, no part of this type: type
PredefinedType: MAIN; NominalDiameter: 0.012 m; CrossSectionArea: 0.0001131 m2; BarLength: 0.0140465 m; Material: Steel

# IfcReinforcingBarType, no part of this type: type
PredefinedType: MAIN; NominalDiameter: 0.012 m; CrossSectionArea: 0.0001131 m2; BarLength: 0.0359998 m; Material: Steel

# IfcReinforcingBarType, no part of this type: type
PredefinedType: MAIN; NominalDiameter: 0.012 m; CrossSectionArea: 0.0001131 m2; BarLength: 0.418 m; Material: Steel

# IfcReinforcingBarType, no part of this type: type
PredefinedType: MAIN; NominalDiameter: 0.012 m; CrossSectionArea: 0.0001131 m2; BarLength: 0.0140465 m; Material: Steel

# IfcReinforcingBarType, no part of this type: type
PredefinedType: MAIN; NominalDiameter: 0.012 m; CrossSectionArea: 0.0001131 m2; BarLength: 0.0359998 m; Material: Steel

# IfcReinforcingBarType, no part of this type: type
PredefinedType: MAIN; NominalDiameter: 0.012 m; CrossSectionArea: 0.0001131 m2; BarLength: 0.423 m; Material: Steel

# IfcReinforcingBarType, no part of this type: type
PredefinedType: MAIN; NominalDiameter: 0.012 m; CrossSectionArea: 0.0001131 m2; BarLength: 0.0140464 m; Material: Steel

# IfcReinforcingBarType, no part of this type: type
PredefinedType: MAIN; NominalDiameter: 0.012 m; CrossSectionArea: 0.0001131 m2; BarLength: 0.0359998 m; Material: Steel

# IfcReinforcingBarType, no part of this type: type
PredefinedType: MAIN; NominalDiameter: 0.012 m; CrossSectionArea: 0.0001131 m2; BarLength: 0.423 m; Material: Steel

# IfcReinforcingBarType, no part of this type: type
PredefinedType: MAIN; NominalDiameter: 0.012 m; CrossSectionArea: 0.0001131 m2; BarLength: 0.0140465 m; Material: Steel

# IfcReinforcingBarType, no part of this type: type
PredefinedType: MAIN; NominalDiameter: 0.012 m; CrossSectionArea: 0.0001131 m2; BarLength: 0.0359998 m; Material: Steel

# IfcReinforcingBarType, no part of this type: type
PredefinedType: MAIN; NominalDiameter: 0.012 m; CrossSectionArea: 0.0001131 m2; BarLength: 0.423 m; Material: Steel

# IfcReinforcingBarType, no part of this type: type
PredefinedType: MAIN; NominalDiameter: 0.012 m; CrossSectionArea: 0.0001131 m2; BarLength: 0.0140465 m; Material: Steel

# IfcReinforcingBarType, no part of this type: type
PredefinedType: MAIN; NominalDiameter: 0.012 m; CrossSectionArea: 0.0001131 m2; BarLength: 0.0359998 m; Material: Steel

# IfcReinforcingBarType, no part of this type: type
PredefinedType: MAIN; NominalDiameter: 0.012 m; CrossSectionArea: 0.0001131 m2; BarLength: 0.423 m; Material: Steel

# IfcReinforcingBarType, no part of this type: type
PredefinedType: MAIN; NominalDiameter: 0.012 m; CrossSectionArea: 0.0001131 m2; BarLength: 0.0140465 m; Material: Steel

# IfcReinforcingBarType, no part of this type: type
PredefinedType: MAIN; NominalDiameter: 0.012 m; CrossSectionArea: 0.0001131 m2; BarLength: 0.0359998 m; Material: Steel

# IfcReinforcingBarType, no part of this type: type
PredefinedType: MAIN; NominalDiameter: 0.012 m; CrossSectionArea: 0.0001131 m2; BarLength: 0.423 m; Material: Steel

# IfcReinforcingBarType, no part of this type: type
PredefinedType: MAIN; NominalDiameter: 0.012 m; CrossSectionArea: 0.0001131 m2; BarLength: 0.0140464 m; Material: Steel

# IfcReinforcingBarType, no part of this type: type
PredefinedType: MAIN; NominalDiameter: 0.012 m; CrossSectionArea: 0.0001131 m2; BarLength: 0.0359998 m; Material: Steel

# IfcReinforcingBarType, no part of this type: type
PredefinedType: MAIN; NominalDiameter: 0.012 m; CrossSectionArea: 0.0001131 m2; BarLength: 0.423 m; Material: Steel

# IfcReinforcingBarType, no part of this type: type
PredefinedType: MAIN; NominalDiameter: 0.012 m; CrossSectionArea: 0.0001131 m2; BarLength: 0.0140465 m; Material: Steel

# IfcReinforcingBarType, no part of this type: type
PredefinedType: MAIN; NominalDiameter: 0.012 m; CrossSectionArea: 0.0001131 m2; BarLength: 0.0359998 m; Material: Steel

# IfcReinforcingBarType, no part of this type: type
PredefinedType: MAIN; NominalDiameter: 0.012 m; CrossSectionArea: 0.0001131 m2; BarLength: 0.425 m; Material: Steel

# IfcReinforcingBarType, no part of this type: type
PredefinedType: MAIN; NominalDiameter: 0.012 m; CrossSectionArea: 0.0001131 m2; BarLength: 0.0140465 m; Material: Steel

# IfcReinforcingBarType, no part of this type: type
PredefinedType: MAIN; NominalDiameter: 0.012 m; CrossSectionArea: 0.0001131 m2; BarLength: 0.0359998 m; Material: Steel

# IfcReinforcingBarType, no part of this type: type
PredefinedType: MAIN; NominalDiameter: 0.012 m; CrossSectionArea: 0.0001131 m2; BarLength: 0.423 m; Material: Steel

# IfcReinforcingBarType, no part of this type: type
PredefinedType: MAIN; NominalDiameter: 0.012 m; CrossSectionArea: 0.0001131 m2; BarLength: 0.0140464 m; Material: Steel

# IfcReinforcingBarType, no part of this type: type
PredefinedType: MAIN; NominalDiameter: 0.012 m; CrossSectionArea: 0.0001131 m2; BarLength: 0.0359998 m; Material: Steel

# IfcReinforcingBarType, no part of this type: type
PredefinedType: MAIN; NominalDiameter: 0.012 m; CrossSectionArea: 0.0001131 m2; BarLength: 0.423 m; Material: Steel

# IfcReinforcingBarType, no part of this type: type
PredefinedType: MAIN; NominalDiameter: 0.012 m; CrossSectionArea: 0.0001131 m2; BarLength: 0.0140465 m; Material: Steel

# IfcReinforcingBarType, no part of this type: type
PredefinedType: MAIN; NominalDiameter: 0.012 m; CrossSectionArea: 0.0001131 m2; BarLength: 0.0359998 m; Material: Steel

# IfcReinforcingBarType, no part of this type: type
PredefinedType: MAIN; NominalDiameter: 0.014 m; CrossSectionArea: 0.00015394 m2; BarLength: 0.97063 m; Material: Steel

# IfcReinforcingBarType, no part of this type: type
PredefinedType: MAIN; NominalDiameter: 0.014 m; CrossSectionArea: 0.00015394 m2; BarLength: 4.03463 m; Material: Steel

# IfcReinforcingBarType, no part of this type: type
PredefinedType: LIGATURE; NominalDiameter: 0.008 m; CrossSectionArea: 0.000050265 m2; BarLength: 1.00815 m; Material: Steel

# IfcReinforcingBarType, no part of this type: type
PredefinedType: MAIN; NominalDiameter: 0.014 m; CrossSectionArea: 0.00015394 m2; BarLength: 0.97063 m; Material: Steel

# IfcReinforcingBarType, no part of this type: type
PredefinedType: MAIN; NominalDiameter: 0.014 m; CrossSectionArea: 0.00015394 m2; BarLength: 4.03463 m; Material: Steel

# IfcReinforcingBarType, no part of this type: type
PredefinedType: LIGATURE; NominalDiameter: 0.008 m; CrossSectionArea: 0.000050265 m2; BarLength: 1.00815 m; Material: Steel

# IfcReinforcingBarType, no part of this type: type
PredefinedType: MAIN; NominalDiameter: 0.014 m; CrossSectionArea: 0.00015394 m2; BarLength: 0.97063 m; Material: Steel

# IfcReinforcingBarType, no part of this type: type
PredefinedType: MAIN; NominalDiameter: 0.014 m; CrossSectionArea: 0.00015394 m2; BarLength: 4.03463 m; Material: Steel

# IfcReinforcingBarType, no part of this type: type
PredefinedType: LIGATURE; NominalDiameter: 0.008 m; CrossSectionArea: 0.000050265 m2; BarLength: 1.00815 m; Material: Steel

# IfcReinforcingBarType, no part of this type: type
PredefinedType: MAIN; NominalDiameter: 0.014 m; CrossSectionArea: 0.00015394 m2; BarLength: 0.97063 m; Material: Steel

# IfcReinforcingBarType, no part of this type: type
PredefinedType: MAIN; NominalDiameter: 0.014 m; CrossSectionArea: 0.00015394 m2; BarLength: 4.03463 m; Material: Steel

# IfcReinforcingBarType, no part of this type: type
PredefinedType: LIGATURE; NominalDiameter: 0.008 m; CrossSectionArea: 0.000050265 m2; BarLength: 1.00815 m; Material: Steel

# IfcReinforcingBarType, no part of this type: type
PredefinedType: MAIN; NominalDiameter: 0.014 m; CrossSectionArea: 0.00015394 m2; BarLength: 0.97063 m; Material: Steel

# IfcReinforcingBarType, no part of this type: type
PredefinedType: MAIN; NominalDiameter: 0.014 m; CrossSectionArea: 0.00015394 m2; BarLength: 4.03463 m; Material: Steel

# IfcReinforcingBarType, no part of this type: type
PredefinedType: LIGATURE; NominalDiameter: 0.008 m; CrossSectionArea: 0.000050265 m2; BarLength: 1.00815 m; Material: Steel

# IfcReinforcingBarType, no part of this type: type
PredefinedType: MAIN; NominalDiameter: 0.014 m; CrossSectionArea: 0.00015394 m2; BarLength: 0.97063 m; Material: Steel

# IfcReinforcingBarType, no part of this type: type
PredefinedType: MAIN; NominalDiameter: 0.014 m; CrossSectionArea: 0.00015394 m2; BarLength: 4.03463 m; Material: Steel

# IfcReinforcingBarType, no part of this type: type
PredefinedType: LIGATURE; NominalDiameter: 0.008 m; CrossSectionArea: 0.000050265 m2; BarLength: 1.00815 m; Material: Steel

# IfcReinforcingBarType, no part of this type: type
PredefinedType: MAIN; NominalDiameter: 0.014 m; CrossSectionArea: 0.00015394 m2; BarLength: 0.97063 m; Material: Steel

# IfcReinforcingBarType, no part of this type: type
PredefinedType: MAIN; NominalDiameter: 0.014 m; CrossSectionArea: 0.00015394 m2; BarLength: 4.03463 m; Material: Steel

# IfcReinforcingBarType, no part of this type: type
PredefinedType: LIGATURE; NominalDiameter: 0.008 m; CrossSectionArea: 0.000050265 m2; BarLength: 1.00814 m; Material: Steel

# IfcReinforcingBarType, no part of this type: type
PredefinedType: MAIN; NominalDiameter: 0.014 m; CrossSectionArea: 0.00015394 m2; BarLength: 0.97063 m; Material: Steel

# IfcReinforcingBarType, no part of this type: type
PredefinedType: MAIN; NominalDiameter: 0.014 m; CrossSectionArea: 0.00015394 m2; BarLength: 4.03463 m; Material: Steel

# IfcReinforcingBarType, no part of this type: type
PredefinedType: LIGATURE; NominalDiameter: 0.008 m; CrossSectionArea: 0.000050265 m2; BarLength: 1.00814 m; Material: Steel

# IfcReinforcingBarType, no part of this type: type
PredefinedType: MAIN; NominalDiameter: 0.014 m; CrossSectionArea: 0.00015394 m2; BarLength: 0.97063 m; Material: Steel

# IfcReinforcingBarType, no part of this type: type
PredefinedType: MAIN; NominalDiameter: 0.014 m; CrossSectionArea: 0.00015394 m2; BarLength: 4.03463 m; Material: Steel

# IfcReinforcingBarType, no part of this type: type
PredefinedType: LIGATURE; NominalDiameter: 0.008 m; CrossSectionArea: 0.000050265 m2; BarLength: 1.00814 m; Material: Steel

# IfcReinforcingBarType, no part of this type: type
PredefinedType: MAIN; NominalDiameter: 0.014 m; CrossSectionArea: 0.00015394 m2; BarLength: 0.97063 m; Material: Steel

# IfcReinforcingBarType, no part of this type: type
PredefinedType: MAIN; NominalDiameter: 0.014 m; CrossSectionArea: 0.00015394 m2; BarLength: 4.03463 m; Material: Steel

# IfcReinforcingBarType, no part of this type: type
PredefinedType: LIGATURE; NominalDiameter: 0.008 m; CrossSectionArea: 0.000050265 m2; BarLength: 1.00814 m; Material: Steel

# IfcReinforcingBarType, no part of this type: type
PredefinedType: MAIN; NominalDiameter: 0.014 m; CrossSectionArea: 0.00015394 m2; BarLength: 0.97063 m; Material: Steel

# IfcReinforcingBarType, no part of this type: type
PredefinedType: MAIN; NominalDiameter: 0.014 m; CrossSectionArea: 0.00015394 m2; BarLength: 4.03463 m; Material: Steel

# IfcReinforcingBarType, no part of this type: type
PredefinedType: LIGATURE; NominalDiameter: 0.008 m; CrossSectionArea: 0.000050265 m2; BarLength: 1.00815 m; Material: Steel

# IfcReinforcingBarType, no part of this type: type
PredefinedType: MAIN; NominalDiameter: 0.014 m; CrossSectionArea: 0.00015394 m2; BarLength: 0.97063 m; Material: Steel

# IfcReinforcingBarType, no part of this type: type
PredefinedType: MAIN; NominalDiameter: 0.014 m; CrossSectionArea: 0.00015394 m2; BarLength: 4.03463 m; Material: Steel

# IfcReinforcingBarType, no part of this type: type
PredefinedType: LIGATURE; NominalDiameter: 0.008 m; CrossSectionArea: 0.000050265 m2; BarLength: 1.00815 m; Material: Steel

# IfcReinforcingBarType, no part of this type: type
PredefinedType: MAIN; NominalDiameter: 0.014 m; CrossSectionArea: 0.00015394 m2; BarLength: 0.97063 m; Material: Steel

# IfcReinforcingBarType, no part of this type: type
PredefinedType: MAIN; NominalDiameter: 0.014 m; CrossSectionArea: 0.00015394 m2; BarLength: 4.03463 m; Material: Steel

# IfcReinforcingBarType, no part of this type: type
PredefinedType: LIGATURE; NominalDiameter: 0.008 m; CrossSectionArea: 0.000050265 m2; BarLength: 1.00814 m; Material: Steel

# IfcReinforcingBarType, no part of this type: type
PredefinedType: MAIN; NominalDiameter: 0.014 m; CrossSectionArea: 0.00015394 m2; BarLength: 0.97063 m; Material: Steel

# IfcReinforcingBarType, no part of this type: type
PredefinedType: MAIN; NominalDiameter: 0.014 m; CrossSectionArea: 0.00015394 m2; BarLength: 4.03463 m; Material: Steel

# IfcReinforcingBarType, no part of this type: type
PredefinedType: LIGATURE; NominalDiameter: 0.008 m; CrossSectionArea: 0.000050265 m2; BarLength: 1.00814 m; Material: Steel

# IfcReinforcingBarType, no part of this type: type
PredefinedType: MAIN; NominalDiameter: 0.014 m; CrossSectionArea: 0.00015394 m2; BarLength: 0.97063 m; Material: Steel

# IfcReinforcingBarType, no part of this type: type
PredefinedType: MAIN; NominalDiameter: 0.014 m; CrossSectionArea: 0.00015394 m2; BarLength: 4.03463 m; Material: Steel

# IfcReinforcingBarType, no part of this type: type
PredefinedType: LIGATURE; NominalDiameter: 0.008 m; CrossSectionArea: 0.000050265 m2; BarLength: 1.00814 m; Material: Steel

# IfcReinforcingBarType, no part of this type: type
PredefinedType: LIGATURE; NominalDiameter: 0.008 m; CrossSectionArea: 0.000050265 m2; BarLength: 1.5868 m; Material: Steel

# IfcReinforcingBarType, no part of this type: type
PredefinedType: MAIN; NominalDiameter: 0.012 m; CrossSectionArea: 0.0001131 m2; BarLength: 3.77121 m; Material: Steel

# IfcReinforcingBarType, no part of this type: type
PredefinedType: MAIN; NominalDiameter: 0.016 m; CrossSectionArea: 0.00020106 m2; BarLength: 2.46833 m; Material: Steel

# IfcReinforcingBarType, no part of this type: type
PredefinedType: MAIN; NominalDiameter: 0.016 m; CrossSectionArea: 0.00020106 m2; BarLength: 2.46833 m; Material: Steel

# IfcReinforcingBarType, no part of this type: type
PredefinedType: LIGATURE; NominalDiameter: 0.008 m; CrossSectionArea: 0.000050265 m2; BarLength: 1.5868 m; Material: Steel

# IfcReinforcingBarType, no part of this type: type
PredefinedType: MAIN; NominalDiameter: 0.012 m; CrossSectionArea: 0.0001131 m2; BarLength: 3.77121 m; Material: Steel

# IfcReinforcingBarType, no part of this type: type
PredefinedType: MAIN; NominalDiameter: 0.016 m; CrossSectionArea: 0.00020106 m2; BarLength: 2.46833 m; Material: Steel

# IfcReinforcingBarType, no part of this type: type
PredefinedType: MAIN; NominalDiameter: 0.016 m; CrossSectionArea: 0.00020106 m2; BarLength: 2.46833 m; Material: Steel

# IfcReinforcingBarType, no part of this type: type
PredefinedType: LIGATURE; NominalDiameter: 0.008 m; CrossSectionArea: 0.000050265 m2; BarLength: 1.5868 m; Material: Steel

# IfcReinforcingBarType, no part of this type: type
PredefinedType: MAIN; NominalDiameter: 0.012 m; CrossSectionArea: 0.0001131 m2; BarLength: 3.77121 m; Material: Steel

# IfcReinforcingBarType, no part of this type: type
PredefinedType: MAIN; NominalDiameter: 0.016 m; CrossSectionArea: 0.00020106 m2; BarLength: 2.46833 m; Material: Steel

# IfcReinforcingBarType, no part of this type: type
PredefinedType: MAIN; NominalDiameter: 0.016 m; CrossSectionArea: 0.00020106 m2; BarLength: 2.46833 m; Material: Steel

# IfcReinforcingBarType, no part of this type: type
PredefinedType: LIGATURE; NominalDiameter: 0.008 m; CrossSectionArea: 0.000050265 m2; BarLength: 1.5868 m; Material: Steel

# IfcReinforcingBarType, no part of this type: type
PredefinedType: MAIN; NominalDiameter: 0.012 m; CrossSectionArea: 0.0001131 m2; BarLength: 4.69121 m; Material: Steel

# IfcReinforcingBarType, no part of this type: type
PredefinedType: MAIN; NominalDiameter: 0.012 m; CrossSectionArea: 0.0001131 m2; BarLength: 4.89121 m; Material: Steel

# IfcReinforcingBarType, no part of this type: type
PredefinedType: MAIN; NominalDiameter: 0.012 m; CrossSectionArea: 0.0001131 m2; BarLength: 3.72121 m; Material: Steel

# IfcReinforcingBarType, no part of this type: type
PredefinedType: MAIN; NominalDiameter: 0.016 m; CrossSectionArea: 0.00020106 m2; BarLength: 4.85045 m; Material: Steel

# IfcReinforcingBarType, no part of this type: type
PredefinedType: MAIN; NominalDiameter: 0.016 m; CrossSectionArea: 0.00020106 m2; BarLength: 5.33546 m; Material: Steel

# IfcReinforcingBarType, no part of this type: type
PredefinedType: MAIN; NominalDiameter: 0.016 m; CrossSectionArea: 0.00020106 m2; BarLength: 2.39333 m; Material: Steel

# IfcReinforcingBarType, no part of this type: type
PredefinedType: MAIN; NominalDiameter: 0.016 m; CrossSectionArea: 0.00020106 m2; BarLength: 2.87833 m; Material: Steel

# IfcReinforcingBarType, no part of this type: type
PredefinedType: LIGATURE; NominalDiameter: 0.008 m; CrossSectionArea: 0.000050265 m2; BarLength: 1.5868 m; Material: Steel

# IfcReinforcingBarType, no part of this type: type
PredefinedType: MAIN; NominalDiameter: 0.012 m; CrossSectionArea: 0.0001131 m2; BarLength: 4.69121 m; Material: Steel

# IfcReinforcingBarType, no part of this type: type
PredefinedType: MAIN; NominalDiameter: 0.012 m; CrossSectionArea: 0.0001131 m2; BarLength: 7.94121 m; Material: Steel

# IfcReinforcingBarType, no part of this type: type
PredefinedType: MAIN; NominalDiameter: 0.016 m; CrossSectionArea: 0.00020106 m2; BarLength: 6.91046 m; Material: Steel

# IfcReinforcingBarType, no part of this type: type
PredefinedType: MAIN; NominalDiameter: 0.016 m; CrossSectionArea: 0.00020106 m2; BarLength: 4.50333 m; Material: Steel

# IfcReinforcingBarType, no part of this type: type
PredefinedType: MAIN; NominalDiameter: 0.016 m; CrossSectionArea: 0.00020106 m2; BarLength: 2.87833 m; Material: Steel

# IfcReinforcingBarType, no part of this type: type
PredefinedType: LIGATURE; NominalDiameter: 0.008 m; CrossSectionArea: 0.000050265 m2; BarLength: 1.5868 m; Material: Steel

# IfcReinforcingBarType, no part of this type: type
PredefinedType: MAIN; NominalDiameter: 0.012 m; CrossSectionArea: 0.0001131 m2; BarLength: 4.74121 m; Material: Steel

# IfcReinforcingBarType, no part of this type: type
PredefinedType: MAIN; NominalDiameter: 0.016 m; CrossSectionArea: 0.00020106 m2; BarLength: 2.95333 m; Material: Steel

# IfcReinforcingBarType, no part of this type: type
PredefinedType: MAIN; NominalDiameter: 0.016 m; CrossSectionArea: 0.00020106 m2; BarLength: 2.95333 m; Material: Steel

# IfcReinforcingBarType, no part of this type: type
PredefinedType: LIGATURE; NominalDiameter: 0.008 m; CrossSectionArea: 0.000050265 m2; BarLength: 1.5868 m; Material: Steel

# IfcReinforcingBarType, no part of this type: type
PredefinedType: MAIN; NominalDiameter: 0.012 m; CrossSectionArea: 0.0001131 m2; BarLength: 4.70121 m; Material: Steel

# IfcReinforcingBarType, no part of this type: type
PredefinedType: MAIN; NominalDiameter: 0.012 m; CrossSectionArea: 0.0001131 m2; BarLength: 6.59121 m; Material: Steel

# IfcReinforcingBarType, no part of this type: type
PredefinedType: MAIN; NominalDiameter: 0.016 m; CrossSectionArea: 0.00020106 m2; BarLength: 6.24045 m; Material: Steel

# IfcReinforcingBarType, no part of this type: type
PredefinedType: MAIN; NominalDiameter: 0.016 m; CrossSectionArea: 0.00020106 m2; BarLength: 3.82834 m; Material: Steel

# IfcReinforcingBarType, no part of this type: type
PredefinedType: MAIN; NominalDiameter: 0.016 m; CrossSectionArea: 0.00020106 m2; BarLength: 2.88333 m; Material: Steel

# IfcReinforcingBarType, no part of this type: type
PredefinedType: LIGATURE; NominalDiameter: 0.008 m; CrossSectionArea: 0.000050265 m2; BarLength: 1.5868 m; Material: Steel

# IfcReinforcingBarType, no part of this type: type
PredefinedType: MAIN; NominalDiameter: 0.012 m; CrossSectionArea: 0.0001131 m2; BarLength: 4.70121 m; Material: Steel

# IfcReinforcingBarType, no part of this type: type
PredefinedType: MAIN; NominalDiameter: 0.012 m; CrossSectionArea: 0.0001131 m2; BarLength: 6.59121 m; Material: Steel

# IfcReinforcingBarType, no part of this type: type
PredefinedType: MAIN; NominalDiameter: 0.016 m; CrossSectionArea: 0.00020106 m2; BarLength: 6.24045 m; Material: Steel

# IfcReinforcingBarType, no part of this type: type
PredefinedType: MAIN; NominalDiameter: 0.016 m; CrossSectionArea: 0.00020106 m2; BarLength: 3.82834 m; Material: Steel

# IfcReinforcingBarType, no part of this type: type
PredefinedType: MAIN; NominalDiameter: 0.016 m; CrossSectionArea: 0.00020106 m2; BarLength: 2.88333 m; Material: Steel

# IfcReinforcingBarType, no part of this type: type
PredefinedType: LIGATURE; NominalDiameter: 0.008 m; CrossSectionArea: 0.000050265 m2; BarLength: 1.5868 m; Material: Steel

# IfcReinforcingBarType, no part of this type: type
PredefinedType: MAIN; NominalDiameter: 0.012 m; CrossSectionArea: 0.0001131 m2; BarLength: 3.37121 m; Material: Steel

# IfcReinforcingBarType, no part of this type: type
PredefinedType: MAIN; NominalDiameter: 0.012 m; CrossSectionArea: 0.0001131 m2; BarLength: 3.32121 m; Material: Steel

# IfcReinforcingBarType, no part of this type: type
PredefinedType: MAIN; NominalDiameter: 0.012 m; CrossSectionArea: 0.0001131 m2; BarLength: 3.39121 m; Material: Steel

# IfcReinforcingBarType, no part of this type: type
PredefinedType: MAIN; NominalDiameter: 0.016 m; CrossSectionArea: 0.00020106 m2; BarLength: 3.90045 m; Material: Steel

# IfcReinforcingBarType, no part of this type: type
PredefinedType: MAIN; NominalDiameter: 0.016 m; CrossSectionArea: 0.00020106 m2; BarLength: 3.89046 m; Material: Steel

# IfcReinforcingBarType, no part of this type: type
PredefinedType: MAIN; NominalDiameter: 0.016 m; CrossSectionArea: 0.00020106 m2; BarLength: 2.22833 m; Material: Steel

# IfcReinforcingBarType, no part of this type: type
PredefinedType: MAIN; NominalDiameter: 0.016 m; CrossSectionArea: 0.00020106 m2; BarLength: 2.21833 m; Material: Steel

# IfcReinforcingBarType, no part of this type: type
PredefinedType: LIGATURE; NominalDiameter: 0.008 m; CrossSectionArea: 0.000050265 m2; BarLength: 1.5868 m; Material: Steel

# IfcReinforcingBarType, no part of this type: type
PredefinedType: MAIN; NominalDiameter: 0.012 m; CrossSectionArea: 0.0001131 m2; BarLength: 3.37121 m; Material: Steel

# IfcReinforcingBarType, no part of this type: type
PredefinedType: MAIN; NominalDiameter: 0.012 m; CrossSectionArea: 0.0001131 m2; BarLength: 3.32121 m; Material: Steel

# IfcReinforcingBarType, no part of this type: type
PredefinedType: MAIN; NominalDiameter: 0.012 m; CrossSectionArea: 0.0001131 m2; BarLength: 3.34121 m; Material: Steel

# IfcReinforcingBarType, no part of this type: type
PredefinedType: MAIN; NominalDiameter: 0.012 m; CrossSectionArea: 0.0001131 m2; BarLength: 4.70121 m; Material: Steel

# IfcReinforcingBarType, no part of this type: type
PredefinedType: MAIN; NominalDiameter: 0.016 m; CrossSectionArea: 0.00020106 m2; BarLength: 3.89046 m; Material: Steel

# IfcReinforcingBarType, no part of this type: type
PredefinedType: MAIN; NominalDiameter: 0.016 m; CrossSectionArea: 0.00020106 m2; BarLength: 3.82545 m; Material: Steel

# IfcReinforcingBarType, no part of this type: type
PredefinedType: MAIN; NominalDiameter: 0.016 m; CrossSectionArea: 0.00020106 m2; BarLength: 4.56545 m; Material: Steel

# IfcReinforcingBarType, no part of this type: type
PredefinedType: MAIN; NominalDiameter: 0.016 m; CrossSectionArea: 0.00020106 m2; BarLength: 2.88333 m; Material: Steel

# IfcReinforcingBarType, no part of this type: type
PredefinedType: MAIN; NominalDiameter: 0.016 m; CrossSectionArea: 0.00020106 m2; BarLength: 2.21833 m; Material: Steel

# Material: Calcestruzzo classe C25/30
Calcestruzzo classe C25/30 - Mass Density: 2500; Poisson Ratio: 0.1; Shear Modulus: 1429420032; Thermal Expansion Coefficient: 0.00001; Young Modulus: 3144719872

# Material: Calcestruzzo classe C25/30
Calcestruzzo classe C25/30 - Mass Density: 2500; Poisson Ratio: 0.1; Shear Modulus: 1429420032; Thermal Expansion Coefficient: 0.00001; Young Modulus: 3144719872

# Material: Calcestruzzo classe C25/30
Calcestruzzo classe C25/30 - Mass Density: 2500; Poisson Ratio: 0.1; Shear Modulus: 1429420032; Thermal Expansion Coefficient: 0.00001; Young Modulus: 3144719872

# Material: Calcestruzzo classe C25/30
Calcestruzzo classe C25/30 - Mass Density: 2500; Poisson Ratio: 0.1; Shear Modulus: 1429420032; Thermal Expansion Coefficient: 0.00001; Young Modulus: 3144719872

# Material: Calcestruzzo classe C25/30
Calcestruzzo classe C25/30 - Mass Density: 2500; Poisson Ratio: 0.1; Shear Modulus: 1429420032; Thermal Expansion Coefficient: 0.00001; Young Modulus: 3144719872

# Material: Calcestruzzo classe C25/30
Calcestruzzo classe C25/30 - Mass Density: 2500; Poisson Ratio: 0.1; Shear Modulus: 1429420032; Thermal Expansion Coefficient: 0.00001; Young Modulus: 3144719872

# Material: Calcestruzzo classe C25/30
Calcestruzzo classe C25/30 - Mass Density: 2500; Poisson Ratio: 0.1; Shear Modulus: 1429420032; Thermal Expansion Coefficient: 0.00001; Young Modulus: 3144719872

# Material: Calcestruzzo classe C25/30
Calcestruzzo classe C25/30 - Mass Density: 2500; Poisson Ratio: 0.1; Shear Modulus: 1429420032; Thermal Expansion Coefficient: 0.00001; Young Modulus: 3144719872

# Material: Calcestruzzo classe C25/30
Calcestruzzo classe C25/30 - Mass Density: 2500; Poisson Ratio: 0.1; Shear Modulus: 1429420032; Thermal Expansion Coefficient: 0.00001; Young Modulus: 3144719872

# Material: Calcestruzzo classe C25/30
Calcestruzzo classe C25/30 - Mass Density: 2500; Poisson Ratio: 0.1; Shear Modulus: 1429420032; Thermal Expansion Coefficient: 0.00001; Young Modulus: 3144719872

# Material: Calcestruzzo classe C25/30
Calcestruzzo classe C25/30 - Mass Density: 2500; Poisson Ratio: 0.1; Shear Modulus: 1429420032; Thermal Expansion Coefficient: 0.00001; Young Modulus: 3144719872

# Material: Calcestruzzo classe C25/30
Calcestruzzo classe C25/30 - Mass Density: 2500; Poisson Ratio: 0.1; Shear Modulus: 1429420032; Thermal Expansion Coefficient: 0.00001; Young Modulus: 3144719872

# Material: Calcestruzzo classe C25/30
Calcestruzzo classe C25/30 - Mass Density: 2500; Poisson Ratio: 0.1; Shear Modulus: 1429420032; Thermal Expansion Coefficient: 0.00001; Young Modulus: 3144719872

# Material: Calcestruzzo classe C25/30
Calcestruzzo classe C25/30 - Mass Density: 2500; Poisson Ratio: 0.1; Shear Modulus: 1429420032; Thermal Expansion Coefficient: 0.00001; Young Modulus: 3144719872

# Material: Calcestruzzo classe C25/30
Calcestruzzo classe C25/30 - Mass Density: 2500; Poisson Ratio: 0.1; Shear Modulus: 1429420032; Thermal Expansion Coefficient: 0.00001; Young Modulus: 3144719872

# Material: Calcestruzzo classe C25/30
Calcestruzzo classe C25/30 - Mass Density: 2500; Poisson Ratio: 0.1; Shear Modulus: 1429420032; Thermal Expansion Coefficient: 0.00001; Young Modulus: 3144719872

# Material: Calcestruzzo classe C25/30
Calcestruzzo classe C25/30 - Mass Density: 2500; Poisson Ratio: 0.1; Shear Modulus: 1429420032; Thermal Expansion Coefficient: 0.00001; Young Modulus: 3144719872

# Material: Calcestruzzo classe C25/30
Calcestruzzo classe C25/30 - Mass Density: 2500; Poisson Ratio: 0.1; Shear Modulus: 1429420032; Thermal Expansion Coefficient: 0.00001; Young Modulus: 3144719872

# Material: Calcestruzzo classe C25/30
Calcestruzzo classe C25/30 - Mass Density: 2500; Poisson Ratio: 0.1; Shear Modulus: 1429420032; Thermal Expansion Coefficient: 0.00001; Young Modulus: 3144719872

# Material: Calcestruzzo classe C25/30
Calcestruzzo classe C25/30 - Mass Density: 2500; Poisson Ratio: 0.1; Shear Modulus: 1429420032; Thermal Expansion Coefficient: 0.00001; Young Modulus: 3144719872

# Material: Calcestruzzo classe C25/30
Calcestruzzo classe C25/30 - Mass Density: 2500; Poisson Ratio: 0.1; Shear Modulus: 1429420032; Thermal Expansion Coefficient: 0.00001; Young Modulus: 3144719872

# Material: Calcestruzzo classe C25/30
Calcestruzzo classe C25/30 - Mass Density: 2500; Poisson Ratio: 0.1; Shear Modulus: 1429420032; Thermal Expansion Coefficient: 0.00001; Young Modulus: 3144719872

# Material: Calcestruzzo classe C25/30
Calcestruzzo classe C25/30 - Mass Density: 2500; Poisson Ratio: 0.1; Shear Modulus: 1429420032; Thermal Expansion Coefficient: 0.00001; Young Modulus: 3144719872

# Material: Calcestruzzo classe C25/30
Calcestruzzo classe C25/30 - Mass Density: 2500; Poisson Ratio: 0.1; Shear Modulus: 1429420032; Thermal Expansion Coefficient: 0.00001; Young Modulus: 3144719872

# Material: Calcestruzzo classe C25/30
Calcestruzzo classe C25/30 - Mass Density: 2500; Poisson Ratio: 0.1; Shear Modulus: 1429420032; Thermal Expansion Coefficient: 0.00001; Young Modulus: 3144719872

# Material: Calcestruzzo classe C25/30
Calcestruzzo classe C25/30 - Mass Density: 2500; Poisson Ratio: 0.1; Shear Modulus: 1429420032; Thermal Expansion Coefficient: 0.00001; Young Modulus: 3144719872

# Material: Calcestruzzo classe C25/30
Calcestruzzo classe C25/30 - Mass Density: 2500; Poisson Ratio: 0.1; Shear Modulus: 1429420032; Thermal Expansion Coefficient: 0.00001; Young Modulus: 3144719872

# Material: Calcestruzzo classe C25/30
